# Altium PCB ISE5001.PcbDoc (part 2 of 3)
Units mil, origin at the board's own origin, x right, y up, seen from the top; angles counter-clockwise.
Board outline 2000 x 3000 mil, 4 copper layers (TOP LAYER, L2_GND-PLANE, L3_PWR-PLANE, BOTTOM LAYER), stack 90 mil thick; 187 components, 138 nets, 683 pads, 415 vias.

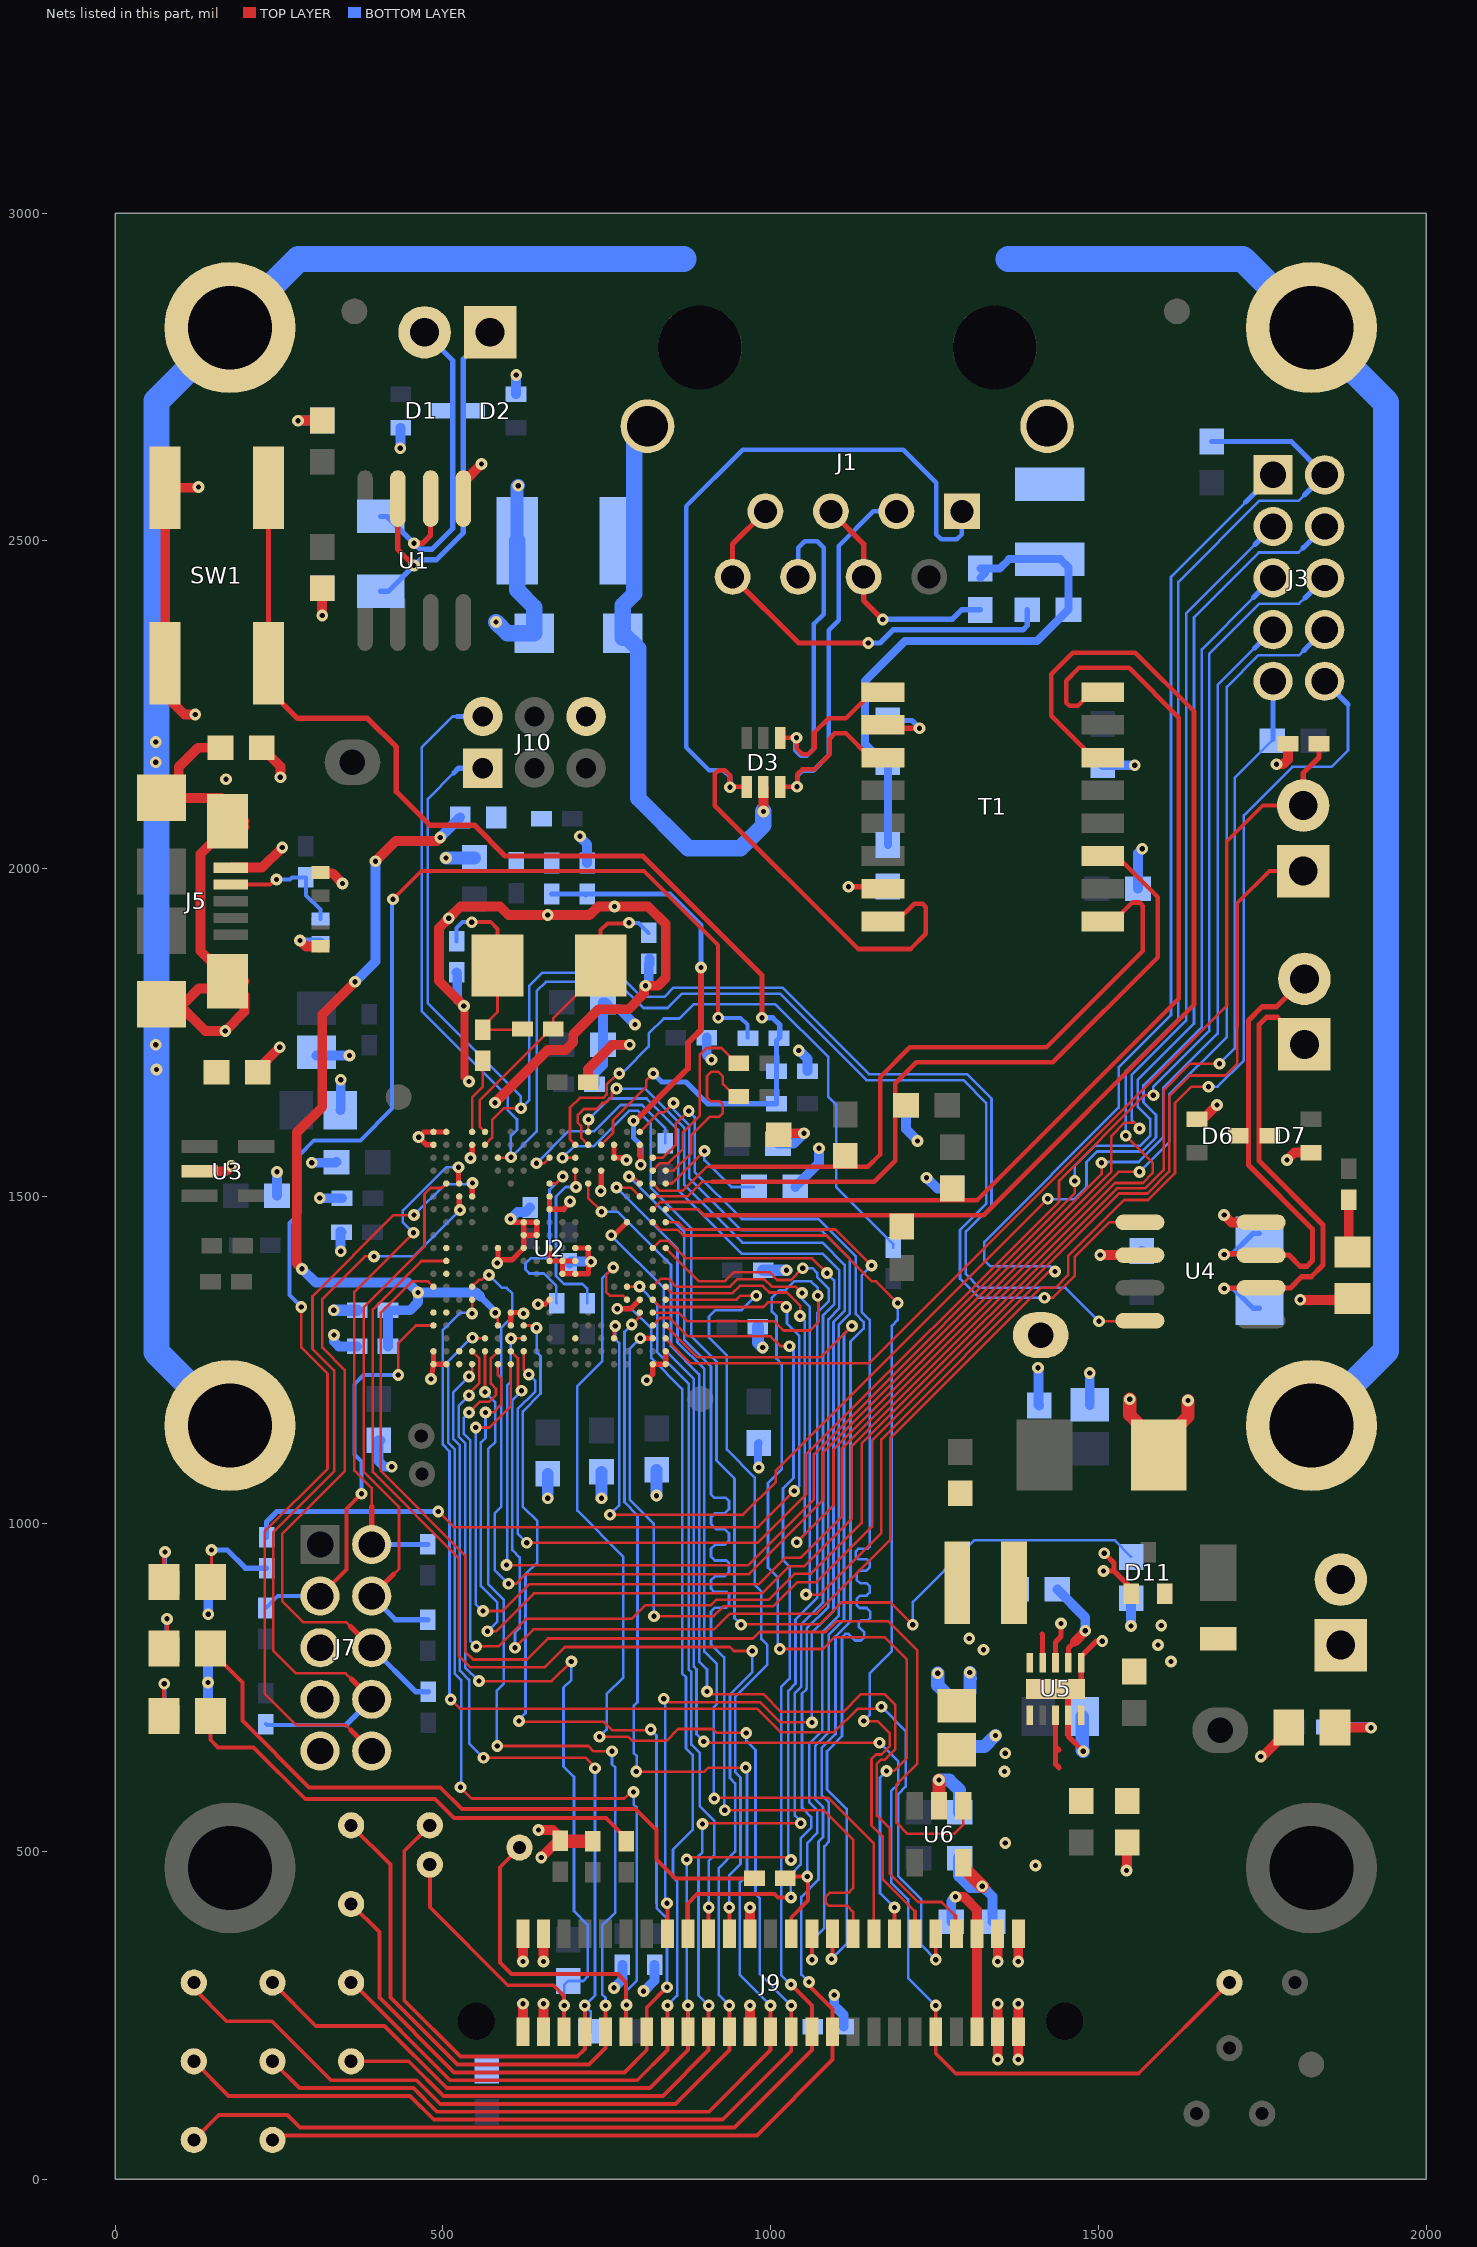
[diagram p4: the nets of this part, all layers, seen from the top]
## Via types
v1: diameter 18, hole 8, TOP LAYER to BOTTOM LAYER, tented both sides, 415 vias

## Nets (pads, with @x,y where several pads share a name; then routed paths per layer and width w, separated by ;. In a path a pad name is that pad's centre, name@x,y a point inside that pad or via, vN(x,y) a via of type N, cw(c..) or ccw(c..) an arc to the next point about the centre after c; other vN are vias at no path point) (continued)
\EXTDBG\: J7.3 R18.2 U2.A4 | length 630.6
  TOP LAYER w4: v1(432,1227) 432,1276 458.68,1302.68 U2.A4@485.55,1302.68
  TOP LAYER w6: J7.3@312.63,889.74 353,930.11 353,1023 v1(376,1046)
  BOTTOM LAYER w6: R18.2@230,871.62 248,889.62 312.51,889.62 J7.3@312.63,889.74 ; v1(376,1046) 376,1095 365,1106 365,1213 379,1227 v1(432,1227)
\HIB\: R49.1 U2.M17 | length 1723.2
  TOP LAYER w4: v1@685.42,1558.58 U2.M17@702.09,1558.58 ; v1@957,847 1075,847 1108,880 1183,880 v1(1217,846)
  BOTTOM LAYER w4: v1(682.42,1558.58) 699.84,1576 730,1576 784,1630 798,1630 817,1611 817,1512.84 879,1450.84 879,1286 917.38,1247.62 917.38,1096.62 945,1069 945,856 v1(955,846) ; v1(1217,846) 1222,846 1217,851 1217,881 1311,975 1524.5,975 R49.1@1550,949.5
\RESET\: C19.1 R38.1 R39.2 SW1.1 SW1.3 U2.P18 | length 1831.4
  TOP LAYER w4: U2.P18@741.46,1578.27 752.72,1589.53 759.47,1596.28 759.47,1616 810.24,1666.76 810.24,1676.24 v1(821,1687)
  TOP LAYER w8: SW1.1@233.74,2562.86 SW1.3@233.74,2313.14 233.74,2273.26 278,2229 385,2229 429,2185 429,2117 480,2066 548,2066 595,2019 805,2019 987,1837 v1(987,1772)
  BOTTOM LAYER w4: R38.1@1012.72,1740.79 R38.1@1014.09,1742.17
  BOTTOM LAYER w8: v1(821,1687) 834,1674 871,1674 904.21,1640.79 R39.2@1009.09,1640.79 C19.1@1009.09,1690.79 1009.09,1737.17 R38.1@1012.72,1740.79 ; v1(987,1772) 1003.38,1772 1014.09,1761.29 R38.1@1014.09,1742.17
\WAKE\: R32.1 R33.2 U2.U18 | length 692
  TOP LAYER w8: U2.U18@800.51,1578.27 800.51,1561.99 802.22,1560.29 802,1560.07 v1(802,1548)
  TOP LAYER w9: v1(791,1615) 794,1615 874,1695 874,1734 894,1754 v1(894,1849)
  BOTTOM LAYER w8: R33.2@666,1961 717,1961 R32.1@718.5,1959.5 ; R32.1@720,1961 846,1961 894,1913 v1(894,1849) ; v1(791,1615) 791,1589 802,1578 v1(802,1548)
ADC0: J3.10 U2.G2 | length 2820.6
  TOP LAYER w4: U2.G2@603.66,1263.31 614.58,1252.39 614.58,1208.42 v1(620,1203) ; v1(610,811) 638,839 914,839 938,863 1070,863 1183,976 1183,1131.21 1411.79,1360 1434.69,1360 1454,1379.31 1454,1408.75 1539.25,1494 1576,1494 1617,1535 1617,1642.03 1641.97,1667 v1(1668,1667)
  BOTTOM LAYER w4: v1(610,811) 610,834 617,841 617,949 606,960 606,1189 v1(620,1203) ; v1(1668,1667) 1682,1667 1722,1707 1722,2081 1796,2155 1856,2155 1881,2180 1881,2249.89
  BOTTOM LAYER w8: J3.10@1845.37,2285.52 1881,2249.89
ADC1: J3.8 U2.G1 | length 2736.8
  TOP LAYER w4: v1(550,1147) 571,1147 603.66,1179.66 U2.G1@603.66,1243.62 ; v1(561,867) 591,867 632,908 982,908 1022,948 1046,948 1109,1011 1109,1115.15 1530.85,1537 v1(1563,1537)
  BOTTOM LAYER w4: v1(550,1147) 550,878 v1(561,867) ; v1(1563,1537) 1608,1582 1608,1655 1696,1743 1696,2277 1744,2325 1806.11,2325 1814.06,2332.94
  BOTTOM LAYER w8: 1814.06,2332.94 J3.8@1845.37,2364.26
ADC2: J3.6 U2.H2 | length 2549.2
  TOP LAYER w4: U2.H2@623.35,1263.31 623.35,1235.65 v1(631,1228) ; v1(628,971) 980,971 1054,1045 1054,1105.41 1440,1491.41 1440,1523.31 1570.69,1654 v1(1584,1654)
  BOTTOM LAYER w4: v1(628,971) 614,985 614,1175 641,1202 641,1218 v1(631,1228) ; v1@1584,1647 v1(1584,1654) 1584,1667 1669,1752 1669,2327 1746,2404 1806.37,2404 1815.19,2412.81
  BOTTOM LAYER w8: 1815.19,2412.81 J3.6@1845.37,2443
ADC3: J3.4 U2.H3 | length 2784.7
  TOP LAYER w4: v1(597,937) 966,937 1066,1037 1066,1106.1 1464,1504.1 v1(1464,1523) ; v1@602.72,1282.79 602.72,1282.99 U2.H3@623.35,1282.99
  BOTTOM LAYER w4: v1(597,937) 598,937 598,1211.31 603.72,1217.03 v1(603.72,1282.79) ; v1@1464,1518 v1(1464,1523) 1464,1546 1495,1577 1564,1577 1579,1592 1579,1618 1560,1637 1560,1677 1646,1763 1646,2383 1745,2482 1805.63,2482 1812.82,2489.18
  BOTTOM LAYER w8: 1812.82,2489.18 J3.4@1845.37,2521.74
CAN0RX: J9.18 TP7.1 U2.W10 | length 2386.6
  TOP LAYER w4: U2.W10@839.88,1420.79 890.67,1370 930,1370 944,1384 998,1384 1010,1372 1031,1372 v1(1049,1390) ; v1(872,488) 872,491 1031,491 v1(1031,487)
  TOP LAYER w6: TP7.1@240,300 306,234 410.88,234 505.88,139 816.02,139 874.02,197 J9.18@874.02,225.2 v1(874.02,264.96)
  BOTTOM LAYER w4: v1(872,488) 872,266.98 v1(874.02,264.96) ; v1(1031,487) 1027,491 1027,745 1038,756 1038,854 1071,887 1071,1322 1089,1340 1089,1358.29 1071,1376.29 1071,1383 1064,1390 v1(1049,1390)
CAN0TX: J9.20 TP14.1 U2.V10 | length 2288.7
  TOP LAYER w4: U2.V10@820.2,1420.79 831.2,1431.79 844.33,1431.79 871.11,1405 1063.5,1405 v1(1086,1382.5) ; v1(896,542) 891,542 892,543 v1(1046,543) v1@1049,543
  TOP LAYER w6: TP14.1@360,180 447.91,180 500.91,127 835.51,127 905.51,197 J9.20@905.51,225.2 v1(905.51,264.96)
  BOTTOM LAYER w4: v1(896,542) 891,542 896,537 896,498.69 890.31,493 890,493 890,280.47 v1(905.51,264.96) ; v1(1046,543) 1049,543 1037,555 1037,742 1047,752 1047,847 1080,880 1080,1318 1097,1335 1097,1371.5 v1(1086,1382.5)
CAN1RX: J10.1 U2.E18 U4.4 | length 2308.8
  TOP LAYER w4: U2.E18@564.29,1578.27 575.21,1589.19 575.21,1616.43 592.79,1634 v1(619,1634) ; v1(1501,1309) 1532.11,1309 1538.11,1315 1558.48,1315 U4.4@1563.48,1310
  BOTTOM LAYER w4: 517,2146 477,2106 477,1794 619,1652 v1(619,1634) 632,1647 632,1821 652,1841 766,1841 803,1804 838,1804 852,1818 1018,1818 1150,1686 1300,1686 1337,1649 1337,1485 1298,1446 1298,1381 1319,1360 1450,1360 v1(1501,1309)
  BOTTOM LAYER w8: 517,2146 524,2153 J10.1@561,2153
CAN1TX: J10.2 U2.F17 U4.1 | length 2514.6
  TOP LAYER w4: U2.F17@583.98,1558.58 603.01,1558.58 v1(603.72,1559.29) ; v1(1418,1345) 1431,1345 1464,1378 1464,1407.43 1516.57,1460 U4.1@1563.48,1460
  BOTTOM LAYER w4: 522,2231.74 514.74,2231.74 468,2185 468,1782 599,1651 599,1631 613,1617 613,1601 603.72,1591.72 v1(603.72,1559.29) 643,1598.57 643,1813 657,1827 766,1827 806,1787 843,1787 865,1809 1014,1809 1146,1677 1294,1677 1329,1642 1329,1488.31 1289,1448.31 1289,1374 1318,1345 v1(1418,1345)
  BOTTOM LAYER w8: 522,2231.74 J10.2@561,2231.74
CANH: D6.3 J6.2 R45.2 U4.7 | length 732.9
  TOP LAYER w8: v1(1692,1411) 1693,1412 1746.52,1412 U4.7@1748.52,1410 1791,1410 1808,1393 1818.37,1393 1827,1401.63 1827,1449.37 1729,1547.37 1729,1768 1750,1789 1772,1789 J6.2@1814.49,1831.49
  BOTTOM LAYER w8: v1(1692,1411) 1692.5,1411.5 1704.5,1411.5 1736.09,1443.09 R45.2@1746,1443.09
CANL: D7.3 J6.1 R45.1 U4.6 | length 730.8
  TOP LAYER w8: v1(1692,1359) 1693,1359 1694,1360 U4.6@1748.52,1360 1793,1360 1810,1377 1825,1377 1843,1395 1843,1456 1745,1554 1745,1761.37 1756.63,1773 1772.97,1773 J6.1@1814.49,1731.49
  BOTTOM LAYER w8: v1(1692,1359) 1706,1359 1736.09,1328.91 R45.1@1746,1328.91
CHGND: C3.2 C8.2 C9.1 D3.2 H1.1 H2.1 H3.1 H4.1 J1.SH1 J1.SH2 J5.6 J5.7 J5.8 J5.9 R7.1 R28.1 | length 6482.7
  TOP LAYER w15: J5.9@97,1792.52 137.52,1752 v1(168,1752) 197.39,1781.39 197.39,1806.61 J5.7@186.72,1817.28 ; J5.9@108,1797 127.48,1816.48 127.48,1817 186.44,1817 J5.7@186.72,1817.28 ; C3.2@160.5,2184 126,2184 97,2155 97,2107.48 161.96,2107.48 J5.6@197.39,2072.05 ; J5.7@197.39,1827.95 J5.7@186.72,1817.28 ; J5.6@197.39,2063.39 171.39,2063.39 130,2022 130,1874 173.72,1830.28 J5.7@186.72,1817.28 ; v1(989,2087) D3.2@989,2124.5
  BOTTOM LAYER w20: J1.SH1@797,2655 J1.SH1@797,2666.73
  BOTTOM LAYER w25: R28.1@774.5,2352 R28.1@774.5,2359 ; J1.SH1@797,2655 791.74,2649.74 791.74,2500 792,2499.74 792,2419 774.5,2401.5 R28.1@774.5,2359 ; v1(989,2087) 989,2066 954,2031 874,2031 798,2107 798,2335.5 R28.1@774.5,2359
  BOTTOM LAYER w40: H3.1@175,1150 63,1262 v1(63,1693) 63,2713 H1.1@175,2825 280,2930 867,2930 ; 1363,2930 1720,2930 H2.1@1825,2825 1939,2711 1939,1264 H4.1@1825,1150
  other v1: 62,1731 169,2136 62,2162 62,2193
COL: J9.15 U2.N18 | length 1967
  TOP LAYER w4: U2.N18@721.77,1578.27 710.85,1589.19 710.85,1606.94 706,1611.79 706,1624 715,1633 734.31,1633 743.31,1642 748.18,1642 758,1651.82 758,1656.69 765,1663.69 v1(765,1664) ; v1(837,733) 838,733 843,728 984,728 1015,697 v1(1063,697)
  TOP LAYER w6: v1(842,421) 842.52,420.48 J9.15@842.52,374.8
  BOTTOM LAYER w4: v1(765,1664) 808.47,1664 868,1604.47 868,1518 957,1429 1079,1429 1113,1395 1113,1325 1096,1308 1096,867 1063,834 v1(1063,697) ; v1(837,733) 839,731 839,424 v1(842,421) v1@842,415.09
CRS: J9.17 U2.N19 | length 1793.8
  TOP LAYER w4: U2.N19@721.77,1597.95 v1@721.77,1623
  TOP LAYER w6: J9.17@874.02,374.8 874.02,421.02 888,435 1006,435 1011,430 v1(1031,430)
  BOTTOM LAYER w4: v1(722,1617) 754,1649 811,1649 859,1601 859,1509 956,1412 1079.69,1412 1105,1386.69 1105,1329 1088,1312 1088,873 1055,840 1055,748.69 1054.5,748.19 1054.5,747.5 1048,741 1048,567 1062,553 1062,536 1046,520 1046,480 1031,465 v1(1031,430)
DEBUG_RX: J4.1 U2.V3 | length 2213.8
  TOP LAYER w4: v1(822,859) 913,859 928,874 1004,874 1041,911 1070,911 1155,996 1155,1127.21 1531.79,1504 1574.69,1504 1608,1537.31 1608,1652 1640,1684 1694,1684 1712,1702 1712,1759
  TOP LAYER w6: 1712,1759 1712,1947 1760.92,1995.92 J4.1@1812.68,1995.92
  TOP LAYER w8: v1@802.22,1282.29 802.92,1282.99 U2.V3@820.2,1282.99
  BOTTOM LAYER w4: v1(801.22,1283.29) 785,1267.07 785,1037 822,1000 v1(822,859)
DEBUG_TX: J4.2 R3.2 U2.W3 | length 1591.3
  TOP LAYER w4: U2.W3@839.88,1282.99 877.87,1245 1149.79,1245 1696,1791.21
  TOP LAYER w6: 1696,1791.21 1696,2041 1750.92,2095.92 J4.2@1812.68,2095.92
  TOP LAYER w8: J4.2@1812.68,2095.92 1812.68,2145.55 1836.62,2169.5 R3.2@1836.62,2190
EN0INTRN: J9.41 U2.D6 | length 1804.8
  TOP LAYER w4: v1(512,732) 526,718 979,718 1015,682 1097,682 1133,718 1166,718 v1(1169,721) ; U2.D6@544.61,1342.05 v1@544.7,1324.76
  TOP LAYER w6: v1(1251.97,335.04) J9.41@1251.97,374.8
  BOTTOM LAYER w4: v1(512,732) 510,734 510,1110.69 500,1120.69 500,1296 526,1322 543,1322 v1(544.22,1320.79) ; v1(1169,721) 1206,684 1206,599 1195,588 1195,462 1230,427 1230,357.01 v1(1251.97,335.04)
EN0RREF_CLK: R43.1 U2.M18 | length 909
  TOP LAYER w4: U2.M18@702.09,1578.27 694,1586.35 694,1635 709,1650 744.87,1650 750,1655.13 750,1670.21 764,1684.21 v1@764,1691
  BOTTOM LAYER w4: v1@764,1691 777,1691 814,1728 814,1748 837,1771 861,1771 883,1793 1007,1793 1088,1712 1088,1651.48 1100,1639.48 1100,1514 1187,1427 R43.1@1187,1421.62
  other v1: 769,1687
EN0RX+: R13.2 T1.6 U2.W13 | length 1827
  TOP LAYER w4: U2.W13@839.88,1479.84 890.16,1479.84 899,1471
  TOP LAYER w7: 899,1471 1325,1471 1646,1792 1646,1820 1646,2237 1646,2239.53 1556.53,2329 1461,2329 1428,2296 1428,2233 1492,2169 T1.6@1506.52,2169
EN0RX-: R11.2 T1.8 U2.V13 | length 1675.9
  TOP LAYER w4: U2.V13@820.2,1479.84 831.35,1491 897,1491 900,1494
  TOP LAYER w7: 900,1494 1315.47,1494 1623,1801.53 1623,2230 1547,2306 1470.53,2306 1451,2286.47 1451,2253 1456,2248 1469,2248 1490,2269 T1.8@1506.52,2269
EN0TX+: R10.2 T1.1 U2.V15 | length 1117.8
  TOP LAYER w4: U2.V15@820.2,1519.21 831.5,1507.91 865.91,1507.91 903,1545 910,1545
  TOP LAYER w7: 910,1545 1148.47,1545 1167,1563.53 1167,1679 1167,1681.53 1212.47,1727 1215,1727 1421,1727 1568,1874 1568,1943 1563,1948 1552,1948 1523,1919 T1.1@1506.52,1919
EN0TX-: R9.2 T1.3 U2.V14 | length 1192.2
  TOP LAYER w4: U2.V14@820.2,1499.53 873.53,1499.53 896,1522 910,1522
  TOP LAYER w7: 911,1522 1158,1522 1190,1554 1190,1672 1222,1704 1428,1704 1430.53,1704 1591,1864.47 1591,1956 1528,2019 T1.3@1506.52,2019
EN0TXER: J9.42 TP9.1 U2.T12 | length 2169.1
  TOP LAYER w4: v1(898,668) 900,666 v1(1166,666)
  TOP LAYER w6: v1(1251.97,264.96) J9.42@1251.97,225.2 1251.97,192.03 1283,161 1561,161 TP9.1@1700,300
  TOP LAYER w8: v1(756.72,1440.29) 760.96,1440.29 U2.T12@780.83,1460.16
  BOTTOM LAYER w4: v1(756.72,1440.29) 837,1360 837,1267 883,1221 883,782 887,778 887,679 v1(898,668) ; v1(1166,666) 1195,637 1195,603 1184,592 1184,453 1210,427 1210,306.93 v1(1251.97,264.96)
GND: C1.2 C2.2 C3.1 C4.2 C5.2 C6.2 C7.2 C9.2 C10.2 C11.2 C12.2 C13.2 C14.1 C15.2 C16.2 C17.2 C18.2 C19.2 C20.2 C21.2 C22.2 C23.2 C24.2 C25.2 C26.2 C27.2 C28.2 C29.2 C30.1 C31.2 C32.2 C33.2 C34.2 C35.2 C36.2 C37.2 C38.2 C39.2 C40.2 C41.2 C42.2 C43.2 C44.2 C45.1 C46.1 C47.1 C48.1 D1.1 D2.1 D4.2 D5.2 D6.1 D7.1 D8.1 D9.2 D11.1 D15.1 D16.2 J5.5 J7.5 J7.7 J7.9 J8.1 J9.23 J9.24 J9.47 J9.48 J9.49 J9.50 J10.6 R3.1 R7.2 R22.2 R28.2 R32.2 R37.1 R41.2 R42.1 R50.2 R53.2 R55.2 R60.1 SW1.2 SW1.4 TL1.1 U1.5 U2.A1 U2.A2 U2.A18 U2.A19 U2.B1 U2.B19 U2.D18 U2.F10 U2.G4 U2.G5 U2.H10 U2.H11 U2.H12 U2.J11 U2.J12 U2.K6 U2.K9 U2.K10 U2.K13 U2.K14 U2.L8 U2.L9 U2.M8 U2.M9 U2.M10 U2.N10 U2.P16 U2.R17 U2.R18 U2.V1 U2.W1 U2.W2 U3.2 U4.2 U4.8 U5.1 U5.4 U5.6 U5.11 U6.2 | length 7010
  TOP LAYER w8: v1(482,1221) U2.A1@485.55,1243.62 ; U2.A2@485.55,1263.31 U2.A1@485.55,1243.62 ; U2.A18@485.55,1578.27 474.73,1578.27 v1(463,1590) 470.95,1597.95 U2.A19@485.55,1597.95 U2.B19@505.24,1597.95 ; U2.B1@505.24,1243.62 U2.A1@485.55,1243.62 ; v1(542,1558) 541,1557 541,1559 544.61,1562.61 U2.D18@544.61,1578.27 ; v1(583,1398) 583.98,1398.98 v1@583.98,1402.79 ; U2.F10@583.98,1420.79 v1@583.98,1402.79 ; v1(603,1465) 607.84,1460.16 U2.H12@623.35,1460.16 ; U2.G4@603.66,1302.68 U2.G5@603.66,1322.36 621.36,1322.36 623,1324 v1(623,1321) ; v1(645,1335) 655.67,1335 U2.K6@662.72,1342.05 ; U2.K10@662.72,1420.79 U2.K9@662.72,1401.1 U2.L9@682.4,1401.1 ; U2.K14@663.46,1498.79 U2.K14@662.72,1499.53 U2.K13@662.72,1479.84 684.16,1479.84 ; 684.72,1479.29 684.16,1479.84 ; v1(694,1492) 694,1490 684,1480 684.16,1479.84 ; U2.M9@702.09,1401.1 U2.L9@682.4,1401.1 ; U2.M10@702.09,1420.79 U2.N10@721.77,1420.79 v1@721.77,1404.23 ; v1@724.9,1401.1 722,1398.2 722,1382 721.42,1381.42 U2.M8@702.09,1381.42 U2.L8@682.4,1381.42 U2.L9@682.4,1401.1 ; v1(741,1508) 741.46,1508.46 U2.P16@741.46,1538.9 ; U2.R18@761.14,1578.27 U2.R17@761.14,1558.58 776.42,1558.58 v1(780,1555) ; v1(811,1219) 820,1228 820.2,1227.8 U2.V1@820.2,1243.62 U2.W1@839.88,1243.62 U2.W2@839.88,1263.31 ; U5.11@1434.7,748 U5.11@1438,748 ; v1(1477,653) 1454.4,675.6 U5.4@1454.4,708 1454.4,741.6 1474.1,761.3 U5.6@1474.1,788 1474.1,798.1 1497,821 v1(1506,821) ; v1(1508,928) 1524,928 ; v1(1509,955) 1524,940 1524,928 ; D11.1@1550.41,893.5 1550.41,901.59 1524,928 ; v1@583.98,1402.79 605.35,1402.79 U2.H10@623.35,1420.79 U2.H11@623.35,1440.47 ; U2.H11@623.35,1440.47 U2.J11@643.03,1440.47 U2.J12@643.03,1460.16 U2.H12@623.35,1460.16 ; U2.H11@623.35,1440.47 U2.H12@623.35,1460.16
  TOP LAYER w12: v1(532,1790) 533,1789 533,1682 v1(540,1675)
  TOP LAYER w15: v1(122,2235) 106,2235 76.26,2264.74 SW1.4@76.26,2313.14 SW1.2@76.26,2580.86 125.86,2580.86 v1(127,2582) ; U3.2@128.7,1538 169,1538 v1(177,1546) ; J5.5@176.32,2001.18 224.18,2001.18 v1(255,2032) ; R7.2@217.5,1689 217.5,1693.5 v1(251,1727) ; C3.1@223.5,2184 252,2155.5 v1(252,2139) ; v1@280,2683 280.5,2683.5 C1.2@316,2683.5 C1.2@320,2683.5 ; v1(282,1890) 291,1881 311.28,1881 D5.2@313,1879.28 ; D4.2@313,1992.72 331.28,1992.72 v1(347,1977) ; v1(316,2386) C2.2@316,2427.5 ; v1@343.62,1677 v1(344.15,1677.53) ; v1(357.46,1714.54) v1@358,1714 ; U1.5@531.22,2564.28 531.22,2589.22 v1(559,2617) ; v1(532,1790) 494,1828 494,1909 v1(509,1924) 527,1942 586.99,1942 599.99,1929 v1(660,1929) 724.01,1929 737.01,1942 v1(762,1942) 813,1942 840,1915 840,1833 828,1821 v1(809,1821) 807,1821 807,1809 783,1785 737,1785 699,1747 699,1735 687,1723 660,1723 v1(579.5,1642.5) ; v1(646,533) 668,533 679,522 C45.1@679,516.62 ; v1(650,491) 676,517 678.62,517 C45.1@679,516.62 ; C45.1@679.5,516.5 C45.1@679.31,516.31 ; C45.1@682.81,512.81 680,515.62 C45.1@679.31,516.31 ; C4.2@721.62,1674 721.62,1693.62 759,1731 v1(785,1731) ; J9.24@968.5,225.2 v1(968.5,264.96) ; J9.23@968.5,374.8 v1(968.5,414.57) ; C5.2@1012.5,1594 1012.5,1596 v1(1051,1596) ; v1(1346.46,182.7) J9.48@1346.46,225.2 v1(1346.46,267.69) ; v1(1346.46,332.31) J9.47@1346.46,374.8 ; v1(1377.95,182.7) J9.50@1377.95,225.2 v1(1377.95,267.69) ; v1(1377.95,332.31) J9.49@1377.95,374.8 ; v1(1503,1410) U4.2@1563.48,1410 ; v1(1543,471) 1543,477.5 1544,478.5 R22.2@1544,514 ; v1(1555.5,2157.5) v1@1556,2158 ; D6.1@1650.5,1617.59 1659.59,1617.59 v1(1681,1639) ; v1(1692,1471) 1703,1460 U4.8@1748.52,1460 ; v1(1748,645) 1748,643 1790.57,685.57 D15.1@1790.57,689 ; v1(1772,2159) 1782,2159 1789.38,2166.38 R3.1@1789.38,2190 ; v1(1788,1555) 1799.41,1566.41 D7.1@1824.5,1566.41 ; v1(1808,1342) 1808.43,1341.57 D8.1@1888,1341.57 ; C45.1@679,516.62 C45.1@679.31,516.31
  TOP LAYER w20: C45.1@680,515.62 C46.1@729,515.62 ; U6.2@1257,570 v1(1257,609) ; v1(1548,1190) 1548,1166 1592.01,1121.99 D9.2@1592.01,1119.01 ; D9.2@1588,1105 D9.2@1592.01,1109.01 ; D9.2@1592.01,1105 D9.2@1592.01,1109.01 ; v1(1637,1188) 1637,1164 D9.2@1592.01,1119.01 ; D9.2@1592.01,1109.01 D9.2@1592.01,1119.01
  BOTTOM LAYER w8: v1@542,1556 v1(542,1558) ; v1@1507,927 v1(1508,928) ; v1(1509,955) v1@1509,958
  BOTTOM LAYER w12: v1(982,1086) 981,1087 981,1122.5 C41.2@982,1123.5
  BOTTOM LAYER w15: R55.2@141.5,705 v1(141.5,758) R53.2@141.5,808 ; R50.2@141.5,909 R50.2@142,909.5 ; v1(142,862) R50.2@142,909.5 ; R42.1@246.8,1500.6 246.8,1536.8 v1(247,1537) ; v1(279,2683) 279.5,2683.5 C7.2@316,2683.5 C7.2@322,2683.5 ; v1(282,1890) 284.72,1887.28 D16.2@313,1887.28 ; v1(300,1551) 336.5,1551 C25.2@337.5,1552 ; C17.2@307,1714.54 v1(357.46,1714.54) ; v1@312,1496.79 C26.2@346.09,1496.79 ; v1(316,2386) C10.2@316,2427.5 ; v1(334,1288) 334,1278 341.21,1270.79 C34.2@369.09,1270.79 ; C21.2@343.46,1631 344.15,1631.69 v1(344.15,1677.53) ; v1(344,1416) 344,1446.38 C29.2@345.38,1445 ; C35.2@402,1127.5 C35.2@402,1124.5 ; C35.2@405,1127.5 C35.2@402,1124.5 ; v1(422,1087) 411,1087 402,1096 C35.2@402,1124.5 ; v1(435,2641) 435.5,2641.5 D1.1@435.5,2672.41 ; C15.2@521,1841.38 522,1840.38 522,1800 v1(532,1790) ; v1(603,1465) 614,1476 626.38,1476 C27.2@633,1482.62 ; D2.1@611.5,2723.59 v1@611.5,2753 ; C28.2@693,1397.38 695.62,1400 v1(726,1400) ; v1(709,2049) 709,2048 720,2037 R32.2@720,2008.24 ; C20.2@731.34,1670.79 731.34,1687.33 744.21,1700.2 C18.2@744.21,1730.79 C18.2@744.21,1731 ; v1(761,292) 774,305 C47.1@774,327.38 ; v1(785,1731) C18.2@744.21,1731 ; v1(793,1762) 770,1785 758,1785 747.21,1795.79 C16.2@744.21,1795.79 C18.2@744.21,1731 ; v1(806,287) 806,286 823,303 C48.1@823,327.38 ; v1(809,1821) 814,1826 C14.1@814,1854.38 ; C14.1@815,1854.38 C14.1@815,1862.38 ; R37.1@902.62,1742 902.62,1715.38 v1(910,1708) ; C23.2@1011.21,1579.79 1034.79,1579.79 v1(1051,1596) ; R41.2@1037.5,1514 1074,1550.5 v1(1074,1573) ; v1(1043,1722) 1043,1723 1056.34,1709.66 C19.2@1056.34,1690.79 ; v1(1097,281) 1097,265 1105.48,256.52 ; 1105.48,256.47 1111.62,250.33 R60.1@1111.62,233 ; C22.2@1206.5,1639 1206.5,1602.5 1224,1585 v1(1224,1584) ; v1(1238,1528) 1254.5,1511.5 C24.2@1277,1511.5 ; v1(1408,1238) 1409,1238 1409,1181.5 C37.2@1410,1180.5 ; C36.2@1487,1181.46 v1(1487,1230) ; v1(1503,1410) 1559.5,1410 C30.1@1566,1416.5 ; C11.2@1507,2157.5 v1(1555.5,2157.5) ; C13.2@1560.5,1969 1560.5,2023.5 v1(1567,2030) ; R50.2@142,909.5 143,910.5 142,911.5 R50.2@142,909.5
  BOTTOM LAYER w18: v1(333.59,1325.79) C32.2@369.09,1325.79 ; v1(660,1039) C40.2@660,1076.5 ; v1(742,1039) C39.2@742,1079.5 ; v1(826,1043) C38.2@826,1082.5 ; C33.2@980.62,1301 980.62,1276.38 v1(988,1269) ; C31.2@988.62,1387 v1(1024.13,1387)
  BOTTOM LAYER w20: v1(504.84,2015.83) C12.2@548.21,2015.83 ; C9.2@613.26,2500 613.26,2582.26 v1(615,2584) ; v1(1257,609) 1273,609 1288.5,593.5 C44.2@1288.5,560 ; C42.2@1285,660.5 1326.5,660.5 v1(1343,677) ; C43.2@1475.56,706.1 1475.56,654.44 v1(1477,653)
  BOTTOM LAYER w25: v1(581,2376) 598,2359 R28.2@639.5,2359 639.5,2398.5 613.26,2424.74 C9.2@613.26,2500
  other v1: 1404,478.5 1358,513 1357,622 1358,650 312,1497 612,2753
I2C6SCL: J3.9 R2.2 U2.F2 | length 2756.9
  TOP LAYER w4: v1(540,1170) 556,1186 570.5,1186 581,1196.5 581,1206 573.06,1213.94 573.06,1252.39 U2.F2@583.98,1263.31 ; v1(551,813) 585,813 627,855 788,855 809,876 909,876 917,884 997,884 1037,924 1062,924 1139,1001 1139,1122.53 1528.47,1512 1571.37,1512 1600,1540.63 1600,1662 1640,1702 v1(1685,1702)
  BOTTOM LAYER w4: v1(540,1170) 532,1162 532,1137 542,1127 542,821 v1@550.5,812.5 ; v1(1685,1702) 1708,1725 1708,2138 R2.2@1766.63,2196.63
  BOTTOM LAYER w8: R2.2@1766.63,2196.63 J3.9@1766.63,2285.52
I2C6SDA: J3.2 R1.2 U2.F1 | length 3252.3
  TOP LAYER w4: v1(565,1170) 577,1170 589,1182 589,1221.68 583.98,1226.7 U2.F1@583.98,1243.62 ; v1(568,836) 581,836 639,894 987,894 1028,935 1051,935 1124,1008 1124,1118.84 1525.16,1520 1568.06,1520 1583,1534.94 1583,1551 v1(1542,1592)
  BOTTOM LAYER w4: v1(565,1170) 565,1131 558,1124 558,905 583,880 583,851 v1(568,836) ; v1(1542,1592) 1542,1691 1622,1771 1622,2437 1746,2561 1805.89,2561 1814.44,2569.56
  BOTTOM LAYER w8: R1.2@1673,2651.5 1794.35,2651.5 J3.2@1845.37,2600.48 1814.44,2569.56
I2C8SCL: J9.6 R59.2 TP4.1 U2.D2 | length 1641.8
  TOP LAYER w4: v1(540,1196) 540,1199.21 555.72,1214.93 555.72,1252.2 U2.D2@544.61,1263.31 ; v1(555,760) 666,760 v1(696,790)
  TOP LAYER w6: TP4.1@480,480 480,415 599,296 668.53,296 685.04,279.49 v1(685.04,264.96) J9.6@685.04,225.2
  BOTTOM LAYER w4: v1(540,1196) 524,1180 524,1133 534,1123 534,781 v1(555,760) ; v1(685.04,264.96) 685.04,296.54 R59.2@691,302.5 714.5,302.5 721,309 721,388 700.04,408.96 700.04,613.96 684,630 684,750 696,762 v1(696,790)
I2C8SDA: J9.8 R61.2 TP2.1 U2.D1 | length 1886.8
  TOP LAYER w4: v1(540,1225) 544.61,1229.61 U2.D1@544.61,1243.62 ; v1(562,643) 718,643 733,628 v1(732,627)
  TOP LAYER w6: TP2.1@480,540 441,501 441,272.97 526.97,187 705,187 716.54,198.54 J9.8@716.54,225.2 v1(716.54,264.96)
  BOTTOM LAYER w4: v1(540,1225) 516,1201 516,1129.37 526,1119.37 526,776 540,762 540,665 v1(562,643) ; R61.2@725.5,226 725.5,255.99 v1(716.54,264.96) 732,280.43 v1(732,627)
LED0: D13.2 R24.2 | length 1035
  TOP LAYER w6: D13.2@144.46,806.03 145.97,806.03 194,758 194,700 296,598 496,598 529,565 794,565 826,533 826,488 855,459 R24.2@975.38,459
LED1: D14.2 R23.2 | length 737.5
  TOP LAYER w4: R23.2@779.53,515.62 R23.2@779.53,520.47
  TOP LAYER w6: D14.2@145.43,707 145.43,670.57 157,659 211,659 290,580 488,580 517,551 749,551 R23.2@779.53,520.47
LED2: D12.2 R48.2 | length 147.1
  TOP LAYER w4: D12.2@144,911 147,914 v1(147,960)
  TOP LAYER w6: D12.2@144,911 D12.2@145.43,911
  BOTTOM LAYER w8: v1(147,960) 171,960 198.62,932.38 R48.2@231,932.38
MCU_ISENSE: U2.A7 U6.1 | length 1831.7
  TOP LAYER w4: U2.A7@485.55,1361.73 477.28,1370 453,1370 405,1322 405,1081 534,952 534,805.31 546.31,793 628,793 660,825 973,825 983,835 1084,835 1100.31,851.31 1179.69,851.31 1224,807 1224,634 1213,623 ; 1203,613 1192,602 1192,544 1209,527 1280,527 1294,541 U6.1@1294,570 ; 1203,613.04 1212.96,623
MDC: J9.21 U2.W6 | length 1234.7
  TOP LAYER w4: U2.W6@839.88,1342.05 948,1342.05 953.95,1348 v1(978,1348)
  TOP LAYER w6: J9.21@937.01,374.8 v1(937.01,414.57)
  BOTTOM LAYER w4: v1(937.01,414.57) 937.01,464.01 954,481 954,613 946,621 946,736 995,785 995,815 986,824 986,897 976,907 976,1071 975.79,1071 933.38,1113.41 933.38,1256.62 906,1284 906,1316 915.91,1325.91 955.91,1325.91 v1(978,1348)
MDIO: J9.19 U2.T7 | length 1056.8
  TOP LAYER w4: U2.T7@781.09,1362 v1(800,1362)
  TOP LAYER w6: J9.19@905.51,374.8 v1(905.51,414.57)
  BOTTOM LAYER w4: v1(800,1362) 827,1335 827,1262 875,1214 875,778 879,774 879,663 892,650 892,569 914,547 914,494 905.51,485.51 v1(905.51,414.57)
MOSC0: C14.2 R5.1 U2.E19 Y1.1 | length 472.5
  TOP LAYER w4: U2.E19@564.29,1597.95 556,1606.24 556,1646 668.62,1758.62 668.62,1771.62 740.74,1843.74 Y1.1@740.74,1852
  TOP LAYER w6: Y1.1@740.74,1852 740.74,1905.74 751,1916 782,1916 v1@784,1914
  BOTTOM LAYER w6: v1(784,1917) 798.62,1917 C14.2@814,1901.62
MOSC1: R4.2 U2.D19 | length 115.2
  TOP LAYER w4: U2.D19@544.61,1597.95 544.61,1650.61 561,1667 R4.2@561,1706.38
NetC6_1: C6.1 C42.1 L1.2 R16.1 R51.1 U5.10 | length 119.1
  BOTTOM LAYER w20: v1(1255,772) 1255,753.5 C42.1@1285,723.5 1304,742.5 1304,763 1305,764 1304,765 v1(1304,773)
  other v1: 1325,808 1303,825
NetC8_1: C8.1 R26.1 R27.1 R29.1 R34.1 | length 845.1
  BOTTOM LAYER w12: R34.1@1179,2035.5 R29.1@1179,2162.5 1171.5,2162.5 1144,2190 1144,2286 1205,2347 1406.5,2347 R27.1@1454.5,2395 1454.5,2459.5 1442.09,2471.91 C8.1@1426,2471.91 1363.91,2471.91 1349.5,2457.5 R26.1@1320,2457.5 ; R26.1@1320,2443.5 R26.1@1327,2450.5
NetC15_1: C15.1 R4.1 R5.2 Y1.2 | length 319.9
  TOP LAYER w4: Y1.2@583.26,1852 583.26,1781.26 561,1759 R4.1@561,1753.62 620,1753.62 R5.2@621.38,1755
  TOP LAYER w6: v1@541,1918 v1(544,1918) 573,1918 583.26,1907.74 Y1.2@583.26,1852
  BOTTOM LAYER w6: C15.1@521,1888.62 521,1909 530,1918 v1(544,1918) v1@546,1918
NetC32_1: C32.1 C34.1 FB1.2 U2.F4 | length 1292.5
  TOP LAYER w4: U2.F4@583.98,1302.68 v1@583.98,1317.95
  TOP LAYER w15: v1(285,1389) 277,1397 277,1597 316,1636 316,1777 v1(366,1827) ; v1(397,2011) 428,2042 491,2042 v1(496,2047)
  BOTTOM LAYER w10: 557,1347 580,1324 v1(580,1322)
  BOTTOM LAYER w15: v1(285,1389) 306,1368 447,1368 v1(462,1353) ; v1(366,1827) 397,1858 v1(397,2011) ; C34.1@416.34,1270.79 C32.1@416.34,1325.79 449.79,1325.79 462,1338 v1(462,1353) ; v1(496,2047) 496,2047.56 FB1.2@526.44,2078 ; 557,1347 551,1353 v1(462,1353)
NetD8_2: D8.2 R12.2 | length 82.4
  TOP LAYER w15: R12.2@1882,1494.38 1882,1420.43 D8.2@1888,1414.43
NetD10_2: D10.2 D11.2 J8.2
  other v1: 1611,790 1591,815 1596,845
NetD12_1: D12.1 R50.1 | length 97.6
  TOP LAYER w4: v1@74.57,957.57 75,958 v1(76,957)
  TOP LAYER w6: D12.1@74.57,911 v1@74.57,957.57
  BOTTOM LAYER w4: R50.1@76,911.5 R50.1@78.5,909
  BOTTOM LAYER w6: R50.1@76,911.5 v1(76,957)
NetD13_1: D13.1 R53.1 | length 94
  TOP LAYER w4: D13.1@74.57,810 D13.1@79,814.43
  TOP LAYER w6: D13.1@79,814.43 v1(79,855)
  BOTTOM LAYER w4: v1@78.5,853.5 79,854 v1(79,855)
  BOTTOM LAYER w6: R53.1@78.5,808 v1@78.5,853.5
NetD14_1: D14.1 R55.1 | length 101.6
  TOP LAYER w4: v1@74.57,755.57 v1(75,756)
  TOP LAYER w6: D14.1@74.57,707 v1@74.57,755.57
  BOTTOM LAYER w4: R55.1@75,708.5 R55.1@78.5,705
  BOTTOM LAYER w6: R55.1@75,708.5 v1(75,756)
NetD15_2: D15.2 R56.2 | length 123.4
  TOP LAYER w15: D15.2@1861.43,689 v1(1916,689)
  BOTTOM LAYER w15: R56.2@1847.62,690 1915,690 v1(1916,689)
NetD16_1: D16.1 J5.4 R35.1 | length 189.9
  TOP LAYER w6: J5.4@176.32,1975.59 236.59,1975.59 v1@244,1983
  BOTTOM LAYER w6: v1(246,1983) 266.62,1983 270,1986.38 R35.1@291,1986.38 291,1959 313,1937 D16.1@313,1922.72
NetFB1_1: FB1.1 R30.1 R31.2 R33.1
NetJ1_4: J1.4 J1.5 R26.2 | length 358.4
  TOP LAYER w8: J1.5@1092,2544.88 1142,2494.88 J1.4@1142,2444.88 1142,2408.92 v1(1171,2379.92)
  BOTTOM LAYER w8: J1.5@1092,2544.88 J1.5@1096,2540.88 ; v1(1171,2379.92) 1171.08,2380 1277,2380 1291.5,2394.5 R26.2@1320,2394.5
NetJ1_7: J1.7 J1.8 R27.2 | length 647.5
  TOP LAYER w8: J1.7@992,2544.88 942,2494.88 J1.8@942,2444.88 1042.88,2344 v1(1149,2344)
  BOTTOM LAYER w8: v1(1149,2344) 1167,2344 1187,2364 1385,2364 1391.5,2370.5 R27.2@1391.5,2395
NetJ9_1: J9.1 J9.2 J9.3 J9.4 R62.2 | length 170
  TOP LAYER w15: J9.2@622.05,225.2 v1(622.05,267.69) ; v1(622.05,332.31) J9.1@622.05,374.8 ; J9.4@653.54,225.2 v1(653.54,267.69) ; v1(653.54,332.31) J9.3@653.54,374.8
NetJ9_45: J9.45 J9.46 R58.1 | length 267.8
  TOP LAYER w15: v1(1282,431) 1295,431 1314.96,411.04 J9.45@1314.96,374.8 J9.46@1314.96,225.2
  BOTTOM LAYER w15: R58.1@1275.5,393 1275.5,424.5 v1(1282,431)
NetL1_1: L1.1 U5.9 | length 44.4
  TOP LAYER w8: 1414,832 1415,831 U5.9@1415,788
NetR6_1: R6.1 U2.V16 | length 287.3
  TOP LAYER w4: U2.V16@820.2,1538.9 831.59,1550.29 844.29,1550.29 866,1572 866,1597 892,1623 892,1716 902,1726 925,1726 948,1703 R6.1@951.38,1703
NetR8_1: R8.1 U2.W16 | length 287
  TOP LAYER w4: U2.W16@839.88,1538.9 851.9,1538.9 879,1566 879,1593 907,1621 921,1621 927,1627 927,1640 922,1645 908.5,1645 903,1650.5 903,1683 910,1690 919.5,1690 927,1682.5 927,1671 946,1652 R8.1@951.38,1652
NetR19_2: R19.2 R49.2 U5.8 | length 106.4
  TOP LAYER w8: U5.8@1434.7,788 1434.7,819.7 1443,828 v1(1443,848)
  BOTTOM LAYER w15: v1(1550,844) R49.2@1550,886.5 ; R49.2@1550,893.5 R49.2@1550.41,893.5
NetR21_2: R21.2 U5.3 | length 89.7
  TOP LAYER w8: U5.3@1434.7,708 1434.7,660.3 ; 1440,628 1434.7,633.3 1434.7,660.3 ; 1440,655 1434.7,660.3
NetR22_1: R22.1 U5.5
NetR29_2: R29.2 T1.10 | length 110.4
  TOP LAYER w8: T1.10@1171.48,2219 1176.48,2214 v1(1227,2214)
  BOTTOM LAYER w8: R29.2@1179,2225.5 1215.5,2225.5 v1(1227,2214)
NetR34_2: R34.2 T1.15 | length 113.9
  TOP LAYER w8: v1(1119,1972) 1168.48,1972 T1.15@1171.48,1969
  BOTTOM LAYER w8: v1(1119,1972) 1119.5,1972.5 R34.2@1179,1972.5
NetR40_1: R40.1 U2.K17 | length 287.4
  TOP LAYER w4: v1@649.57,1550 654.13,1550 U2.K17@662.72,1558.58
  BOTTOM LAYER w4: v1(643,1550) 692,1599 731,1599 771,1639 804,1639 839,1604 R40.1@839,1580.62
NetR41_1: R41.1 U2.W15 | length 186.2
  TOP LAYER w4: U2.W15@839.88,1519.21 849.21,1519.21 v1(899,1569)
  BOTTOM LAYER w4: v1(899,1569) 899,1555 940,1514 R41.1@974.5,1514
NetR46_1: R46.1 U2.M16 | length 260.7
  TOP LAYER w4: v1@702.09,1514.87 U2.M16@702.09,1538.9 ; v1@702.11,1514.89 v1@703,1515.79
  BOTTOM LAYER w4: v1(703,1514) 687,1514 672.5,1499.5 672.5,1378.5 685,1366 713,1366 720,1359 R46.1@720,1336.62
NetR47_1: R47.1 U2.K15 | length 287.4
  TOP LAYER w4: U2.K15@662.72,1519.21 672.21,1519.21 v1(683,1530)
  BOTTOM LAYER w4: R47.1@674,1336.62 672.72,1337.91 672.72,1363.28 654,1382 632,1382 626,1388 626,1397 634,1405 656,1405 662.72,1411.72 662.72,1509.72 v1(683,1530)
NetR51_2: R51.2 U5.7 | length 140.2
  TOP LAYER w8: U5.7@1454.4,788 1454.4,810.4 1464,820
  TOP LAYER w15: 1464,820 1480,836 v1(1480,837)
  BOTTOM LAYER w15: R51.2@1437.5,900 1480,857.5 v1(1480,837)
NetR57_1: R57.1 R58.2 U6.5 | length 176.3
  TOP LAYER w20: U6.5@1294,483 1294,476 v1(1323,447)
  BOTTOM LAYER w15: v1(1323,447) 1338.5,431.5 R58.2@1338.5,393
  BOTTOM LAYER w20: R57.1@1288.5,490 1288.5,463.5 1305,447 v1(1323,447)
PD0/AIN15: U2.C2
PD1/T0CCP0: U2.C1
PE4: U2.A5
PF1/LED2: R48.1 U2.V6 | length 1373.3
  TOP LAYER w4: v1(493,1019) 517,995 981,995 v1(1036,1050) ; U2.V6@820.2,1342.05 831.46,1330.79 988.79,1330.79 996,1338 1017,1338 v1(1024,1331)
  BOTTOM LAYER w4: v1@1025,1330 1025,1305.79 1044,1286.79 1044,1058 v1(1036,1050)
  BOTTOM LAYER w8: R48.1@231,979.62 231,1003 247,1019 v1(493,1019)
PG0/PPS: J9.43 U2.N15 | length 1618.3
  TOP LAYER w4: U2.N15@721.77,1519.21 721.77,1497.23 742,1477 v1(742,1476) ; v1(903,744) 907,740 989,740 1016,713 1111,713 1138,740 1174,740 1190,724 1190,656 1174,640 1168,640 1162,634 1162,555 1182,535 1182,466 1225,423 1261,423 1282,402 ; J9.43@1282,376.27 J9.43@1283.46,374.8
  TOP LAYER w6: J9.43@1282,376.27 1282,402
  BOTTOM LAYER w4: v1(742,1476) 767,1476 848,1395 848,1271 891,1228 891,790 903,778 v1(903,744)
PP6: U2.B8
PQ7/LED_G: U2.M3
RESET_N: J9.22 TP6.1 U2.B9 | length 2772.2
  TOP LAYER w4: TP6.1@120,291 TP6.1@120,300 ; U2.B9@505.24,1401.1 467.1,1401.1 393,1327 393,1079 524,948 524,799 542,781 655,781 686,812 938,812 944,806 v1(972,806)
  TOP LAYER w6: TP6.1@120,291 170,241 239,241 329,151 459.94,151 495.94,115 855.01,115 937.01,197 J9.22@937.01,225.2 v1(937.01,264.96)
  BOTTOM LAYER w4: v1(937.01,264.96) 921,280.97 921,475 946,500 946,604 938,612 938,739.31 972,773.31 v1(972,806)
RS485-A: D1.3 J2.2 R25.2 U1.6 | length 547.4
  TOP LAYER w8: v1(456,2496) 469,2496 481.22,2508.22 U1.6@481.22,2564.28
  BOTTOM LAYER w8: R25.2@405,2537.09 414.91,2537.09 v1(456,2496) 465,2487 483.37,2487 515,2518.63 515,2775 J2.2@472,2818
RS485-B: D2.3 J2.1 R25.1 U1.7 | length 598.4
  TOP LAYER w8: U1.7@431.22,2564.28 431.22,2486.78 v1(456,2462)
  BOTTOM LAYER w8: R25.1@405,2422.91 416.91,2422.91 v1(456,2462) 465,2471 490,2471 531,2512 531,2777 J2.1@572,2818
RX+_RJ45: D3.3 J1.3 T1.11 | length 744.8
  TOP LAYER w7: D3.3@1014.59,2124.5 v1(1040.4,2124.5) 1040.4,2143.4 1048,2151 1067,2151 1090,2174 1090,2198 1098,2206 1115,2206 1152,2169 T1.11@1171.48,2169
  BOTTOM LAYER w7: v1(1040.4,2124.5) 1040.4,2141.4 1048,2149 1065,2149 1089,2173 1089,2363.47 1104,2378.47 1104,2492 1156.88,2544.88 J1.3@1192,2544.88
RX-_RJ45: D3.4 J1.6 T1.9 | length 687.5
  TOP LAYER w7: D3.4@1014.59,2199.31 v1(1039.6,2199.31) 1039.6,2182.93 1048.53,2174 1057.47,2174 1067,2183.53 1067,2207.53 1088.47,2229 1115,2229 1155,2269 T1.9@1171.48,2269
  BOTTOM LAYER w7: v1@1037.41,2197.12 1037.41,2180.59 1046,2172 1055.47,2172 1066,2182.53 1066,2373 1081,2388 1081,2489 1071,2499 1052,2499 1042,2489 J1.6@1042,2444.88
RX_CLK: J9.37 U2.V5 | length 1631.1
  TOP LAYER w4: U2.V5@820.2,1322.36 820.56,1322 828.93,1322 828.97,1321.96 833.94,1321.96 833.98,1322 860,1322 873,1309 1006,1309 1020,1295 1060,1295 1073,1308 1073,1347 v1(1072,1348) ; v1(1014,809) 1079.69,809 1097.69,827 1174,827 1208,793 1208,643 1188,623 v1(1177,623)
  TOP LAYER w6: J9.37@1188.98,374.8 v1(1188.98,414.57)
  BOTTOM LAYER w4: v1(1014,809) 1011,812 1011,918 996,933 996,1062 1017,1083 1017,1244 1009,1252 1009,1317 1002,1324 1002,1345 1013,1356 1022,1356 1036,1370 1062,1370 1072,1360 v1(1072,1348) ; v1(1177,623) 1167,613 1167,436.54 v1(1188.98,414.57)
RX_DV: J9.35 U2.U14 | length 1447.9
  TOP LAYER w4: v1(765,1513) 787.04,1513 U2.U14@800.51,1499.53 ; v1(914,581) 915,582 1088,582 1157.48,512.52 J9.35@1157.48,374.8
  BOTTOM LAYER w4: v1(765,1513) 858,1420 858,1277 899,1236 899,805 918,786 918,725 913,720 v1@913,582
RX_ER: J9.39 U2.V12 | length 1481.4
  TOP LAYER w4: U2.V12@820.2,1460.16 831.57,1448.79 858.21,1448.79 867,1440 1085,1440 1155,1370 1161,1370 v1(1194,1337) ; v1(1142,699) 1163,699 1182,680 1182,660.79 1169.21,648 1161,648 1154,641 1154,540 1171,523 1171,458 1220.47,408.53
  TOP LAYER w6: J9.39@1220.47,374.8 1220.47,408.53
  BOTTOM LAYER w4: v1(1142,699) 1151,708 1151,772 1185,806 1185,1302 1194,1311 v1(1194,1337)
RXD0: J9.31 U2.W12 | length 1630
  TOP LAYER w4: U2.W12@839.88,1460.16 858.84,1460.16 870,1449 1099,1449 v1(1154,1394) ; v1(1093,336) v1@1094.49,337.49
  TOP LAYER w6: v1@1094.49,337.49 J9.31@1094.49,374.8
  BOTTOM LAYER w4: v1(1093,336) 1116,359 1116,565 1086,595 1086,653 1109,676 1109,827 1114,832 1119,832 1129,822 1138,822 1143,827 1143,834 1134.5,842.5 1134.5,848.5 1138.5,852.5 1148.5,852.5 1152,856 1152,866 1146.5,871.5 1136,871.5 1131.33,876.17 1131.33,885.33 1136.5,890.5 1146.5,890.5 1151,895 1151,905 1146.5,909.5 1136.5,909.5 1131.33,914.67 1131.33,924 1135.83,928.5 1146,928.5 1151,933.5 1151,941 1146,946 1134,946 1130,950 1130,958 1134,962 1148,962 1151,965 1151,1311 1139,1323 1139,1379 v1(1154,1394)
RXD1: J9.33 U2.U15 | length 1640.9
  TOP LAYER w4: v1(784,1530) 789.72,1530 U2.U15@800.51,1519.21 ; v1(930,563) 1081,563 1125.98,518.02 1125.98,444 1118.98,437 1090,437 1084,431 1084,422 1089,417 1116.98,417 1125.98,408 J9.33@1125.98,374.8
  BOTTOM LAYER w4: v1(784,1530) 868,1446 868,1281 909,1240 909,1045 914,1040 931.44,1040 936.44,1035 936.44,1022.44 930,1016 915,1016 909,1010 909,1000 917,992 930,992 936.44,985.56 936.44,974.44 930,968 915,968 909,962 909,950 915,944 932.44,944 936.44,940 936.44,926.44 930,920 915,920 909,914 909,901 914,896 933,896 936.44,892.56 936.44,876.44 932,872 915,872 909,866 909,816 929,796 929,564 v1(930,563)
RXD2: J9.29 U2.V17 | length 1658.9
  TOP LAYER w4: U2.V17@820.2,1558.58 835.58,1558.58 844.35,1567.35 844.41,1567.35 850.8,1573.74 850.8,1573.8 855,1578 855,1610 v1(875,1630)
  TOP LAYER w6: v1(1063,335) J9.29@1062.99,374.8
  BOTTOM LAYER w4: v1(875,1630) 884,1621 884,1537 956,1465 1073,1465 1130,1408 1130,1320 1142,1308 1142,1298 1122,1278 1122,851.31 1099,828.31 1099,679 1078,658 1078,586 1089,575 1089,515 1082,508 1082,383 1063,364 v1(1063,335)
RXD3: J9.27 R24.1 U2.U19 | length 1604.4
  TOP LAYER w4: U2.U19@800.51,1597.95 830.56,1628 838,1628 v1(852,1642) ; R24.1@1022.62,459 R24.1@1025.62,462 ; v1(1056,462) 1051,462 v1@1057,456
  TOP LAYER w6: R24.1@1025.62,462 v1@1051,462 ; J9.27@1031.5,374.8 1031.5,399.5 1057,425 v1@1057,456
  BOTTOM LAYER w4: v1(852,1642) 852,1632 860,1624 860,1623.79 876,1607.79 876,1527 955,1448 1077,1448 1121,1404 1121,1321 1104,1304 1104,860 1079,835 1079,685 1059,665 1059,575 1071,563 1071,528 1056,513 v1(1056,462)
SPARE1: J3.1 U2.V7 | length 2882.6
  TOP LAYER w4: U2.V7@820.2,1361.73 832.46,1374 844,1374 856,1362 938,1362 949,1373 991,1373 1002,1362 1038,1362 v1(1048,1352) ; v1(1054,892) 1075,892 1169,986 1169,1129 1425,1385 v1(1434,1385)
  BOTTOM LAYER w4: v1(1048,1352) 1048,1343 1060,1331 1060,898 v1(1054,892) ; v1(1434,1385) 1426,1393 1335,1393 1326,1402 1326,1430 1531,1635 1531,1696 1611,1776 1611,2444.85 1725.07,2558.93
  BOTTOM LAYER w8: 1725.07,2558.93 J3.1@1766.63,2600.48
SPARE2: J3.3 U2.W7 | length 2475.8
  TOP LAYER w4: U2.W7@839.88,1361.73 849.61,1352 942,1352 953,1363 988,1363 998,1353 1025,1353 1045,1333 v1(1045,1317) ; v1(1040,972) 1096,1028 1096,1113.47 1520,1537.47 1520,1592 1540,1612 1555,1612 v1@1559,1608
  BOTTOM LAYER w4: v1(1040,972) 1052,984 1052,1310 v1(1045,1317) ; v1(1563,1603) 1563,1604 1551,1616 1551,1685 1634,1768 1634,2389.11 1738.94,2494.06
  BOTTOM LAYER w8: 1738.94,2494.06 J3.3@1766.63,2521.74
SPARE3: J3.5 U2.R3 | length 2358.6
  TOP LAYER w4: v1(755,1014) 958,1014 1008,1064 1008,1081 v1(1423,1496) ; U2.R3@761.14,1282.99 v1@761.14,1297.14
  BOTTOM LAYER w4: v1(755,1014) 769,1028 769,1276 763,1282 v1(763,1302) ; v1(1423,1496) 1423,1495 1463,1495 1482,1514 1482,1552 1498,1568 1566.31,1568 1588,1589.69 1588,1624 1569,1643 1569,1669 1658,1758 1658,2334.37 1736.82,2413.18
  BOTTOM LAYER w8: 1736.82,2413.18 J3.5@1766.63,2443
SPARE4: J3.7 U2.D7 | length 2723.6
  TOP LAYER w4: U2.D7@544.61,1361.73 555,1372.13 559.24,1372.13 566.77,1379.65 v1(570.23,1379.65) ; v1(600,908.44) 611.23,908.44 626,923.21 967.21,923.21 1080,1036 1080,1108.78 1505,1533.78 v1(1505,1551)
  BOTTOM LAYER w4: v1(570.23,1379.65) 589.89,1360 597.21,1360 606,1351.21 606,1316 589,1299 589,1289.28 588.72,1289 588.72,1276.57 589,1276.29 589,1026 579,1016 579,929.44 v1(600,908.44) ; v1@1503,1551 v1(1505,1551) 1506,1552 1561.63,1552 1599,1589.37 1599,1665 1682,1748 1682,2279.63 1738.69,2336.31
  BOTTOM LAYER w8: 1738.69,2336.31 J3.7@1766.63,2364.26
SPARE5: U2.B10
SPARE6: U2.B5
SPI0CS: J9.26 TP13.1 U2.U5 | length 2179.5
  TOP LAYER w4: v1(788,1304) 800.51,1316.51 U2.U5@800.51,1322.36 ; v1(795,622) 899,622 905,628 v1(962,628)
  TOP LAYER w6: TP13.1@240,180 281,139 454.97,139 490.97,103 906,103 1000,197 J9.26@1000,225.2 v1(1000,264.96)
  BOTTOM LAYER w4: v1(788,1304) 777,1293 777,1033 797,1013 797,727.79 791,721.79 791,650.69 796,645.69 796,623 v1(795,622) ; v1(962,628) 964,626 964,464 953,453 953,311.96 v1(1000,264.96)
SPI0SCK: J9.28 TP12.1 U2.T6 | length 2603
  TOP LAYER w4: v1(739,675) 783,675 789,669 841,669 859,687 912,687 918,681 v1(963,681) ; v1(760,1391) 749,1380 749,1354 755,1348 774.87,1348 U2.T6@780.83,1342.05
  TOP LAYER w6: TP12.1@120,180 173,127 450,127 486,91 927,91 1031.5,195.5 J9.28@1031.5,225.2 v1(1031.5,264.96)
  BOTTOM LAYER w4: v1(739,675) 750,686 750,740 775,765 775,950 705,1020 705,1210 743,1248 743,1374 v1(760,1391) ; v1(963,681) 963,669 977,655 977,435 983.5,428.5 983.5,312.95 v1(1031.5,264.96)
SPI0SDI: J9.32 TP18.1 U2.W4 | length 2410.4
  TOP LAYER w4: U2.W4@839.88,1302.68 888.56,1254 1076,1254 v1(1124,1302)
  TOP LAYER w6: TP18.1@240,60 247,67 979,67 1094.49,182.49 J9.32@1094.49,225.2 1094.49,259.51 1058.45,295.55 v1(1058.45,301)
  BOTTOM LAYER w4: v1(1058.45,301) 1047,312.45 1047,431 1073,457 1073,515 1080,522 1080,568 1068,580 1068,661 1089,682 1089,831 1112,854 1112,1290 v1(1124,1302)
SPI0SDO: J9.30 R60.2 TP17.1 U2.V4 | length 2436.1
  TOP LAYER w4: U2.V4@820.2,1302.68 831.48,1313.96 837.26,1313.96 837.3,1314 846,1314 874,1286 1000,1286 1015,1271 v1(1029,1271)
  TOP LAYER w6: TP17.1@120,60 158,98 263,98 282,79 944.99,79 1062.99,197 J9.30@1062.99,225.2 1062.99,264.96 v1(1031,297)
  BOTTOM LAYER w4: v1(1029,1271) 1035,1265 1035,1070.21 1019,1054.21 1019,945 1029,935 1029,764 1016,751 1016,311.95 1062.99,264.96 R60.2@1062.99,233
SPI3CS: J9.10 TP1.1 U2.E2 | length 1942.7
  TOP LAYER w4: v1(564.29,1201) 564.29,1249.46 564.48,1249.65 564.23,1249.9 564.23,1254.87 564.29,1254.94 U2.E2@564.29,1263.31 ; v1(583,661) 722,661 730,653 v1(758,653)
  TOP LAYER w6: TP1.1@360,540 420,480 420,277 522,175 723,175 748.03,200.03 J9.10@748.03,225.2 v1(748.03,264.96)
  BOTTOM LAYER w4: v1(564.29,1201) 580,1185.29 580,1125 569,1114 569,908 593,884 593,756 582,745 v1@582,662 ; v1@582,660 v1@582,662 ; v1(583,661) v1@582,662 ; v1(748.03,264.96) 748.03,276.97 743,282 743,387 763.03,407.03 763.03,628 758,633.03 v1(758,653)
SPI3SCK: J9.12 TP3.1 U2.E3 | length 1803.8
  TOP LAYER w4: v1(527,598) 544,581 777,581 v1@789,593 ; v1@547.92,1282.99 U2.E3@564.29,1282.99
  TOP LAYER w6: TP3.1@617,506 587,476 587,331 605,313 767,313 779.53,300.47 v1@779.53,266.47 ; J9.12@779.53,225.2 v1@779.53,266.47 ; v1(780,266) v1@779.53,266.47
  BOTTOM LAYER w4: v1(527,598) 528,598 528,762 518,772 518,1114 508,1124 508,1248 544,1284 v1(545,1284) ; v1(780,266) 780,287 796,303 796,567 791,572 v1(791,591)
SPI3SDI: J9.16 TP8.1 U2.U6 | length 1816.5
  TOP LAYER w6: TP8.1@360,300 361.85,300 510.85,151 796.52,151 842.52,197 J9.16@842.52,225.2 v1(842.52,264.96)
  TOP LAYER w8: v1(766,1328) 786.46,1328 U2.U6@800.51,1342.05
  BOTTOM LAYER w4: v1(766,1328) 788,1328 818,1298 818,1253 865,1206 865,772 871,766 871,657.53 881,647.53 881,533 851,503 851,461 857.52,454.48 857.52,279.96 v1(842.52,264.96)
SPI3SDO: J9.14 TP5.1 U2.H4 | length 2005.1
  TOP LAYER w4: v1(616,699) 617,698 746,698 750,694 750,693.79 758.79,685 816,685 v1@816.89,685.89 ; U2.H4@623.35,1302.68 639.32,1302.68 v1(643,1299)
  TOP LAYER w6: TP5.1@360,420 403,377 403,277 511,169 ; 511.03,169 517.03,163 777.02,163 811.02,197 J9.14@811.02,225.2 811.02,262.02 v1(842,293)
  BOTTOM LAYER w4: v1(616,699) 616,701 626,711 626,923.21 644,941.21 644,1004 622,1026 622,1171.69 649,1198.69 649,1256 643,1262 v1(643,1299) ; v1(817,686) 826,677 826,420.8 826.02,413.98 842,398 v1(842,293)
T_TRST: J7.10 R38.2 | length 2335.7
  TOP LAYER w4: v1(284,1331) 284,1269 324,1229 324,1084 228,988 228,741 276,693 351.89,693 359.89,685
  TOP LAYER w6: v1(424,1953) 467,1996 807,1996 920,1883 v1(920,1772)
  TOP LAYER w8: 359.89,685 J7.10@391.37,653.52
  BOTTOM LAYER w4: R38.2@964.53,1741.73 R38.2@965.47,1740.79
  BOTTOM LAYER w6: v1@422.5,1951.5 422.5,1633.5 374,1585 303,1585 281,1563 281,1474 266,1459 266,1349 v1(284,1331) ; v1(920,1772) 954.26,1772 964.53,1761.73 R38.2@964.53,1741.73 ; v1(284,1331) 288,1331 284,1327 v1(284,1331)
TCK: J7.4 R20.2 U2.B15 | length 831.9
  TOP LAYER w4: 424.63,923 433,931.37 433,1026 379,1080 379,1330 472,1423 472,1503 481.45,1512.45 498.47,1512.45 U2.B15@505.24,1519.21
  TOP LAYER w8: J7.4@391.37,889.74 424.63,923
  BOTTOM LAYER w8: J7.4@391.37,889.74 427.49,853.62 R20.2@477,853.62
TDI: J7.8 R52.2 U2.D14 | length 1296.8
  TOP LAYER w4: 360.63,763 351.63,772 276,772 241,807 241,987 334,1080 334,1234 301,1267 301,1347 425,1471 v1(456,1471)
  TOP LAYER w8: 360.63,763 J7.8@391.37,732.26 ; U2.D14@544.61,1499.53 544.61,1515.6 v1@547,1518
  BOTTOM LAYER w4: v1(456,1471) 454,1471 453,1472 457,1472 503,1518 547,1518 v1(545,1520)
  BOTTOM LAYER w6: R52.2@230,694.38 231.38,693 352.11,693
  BOTTOM LAYER w8: 352.11,693 J7.8@391.37,732.26
TDO: J7.6 R54.2 U2.C14 | length 1082.3
  TOP LAYER w4: 359.19,843.19 352.37,850 286.63,850 255,881.63 255,985 350,1080 350,1235 316,1269 316,1343 381,1408 v1(395,1408)
  TOP LAYER w8: 359.19,843.19 J7.6@391.37,811 ; U2.C14@524.92,1499.53 524.92,1480.08 v1(526,1479)
  BOTTOM LAYER w4: v1(395,1408) 455,1408 v1(526,1479)
  BOTTOM LAYER w8: J7.6@391.37,811 458.75,743.62 R54.2@478,743.62
TMS: J7.2 R17.2 U2.C15 | length 787.3
  TOP LAYER w4: 391.37,1026 391.37,1054.63 365,1081 365,1354 v1(455,1444)
  TOP LAYER w8: J7.2@391.37,968.48 391.37,1026 ; v1(524,1544) 524,1520.13 U2.C15@524.92,1519.21
  BOTTOM LAYER w4: v1(455,1444) 439,1460 439,1478 505,1544 v1(524,1544)
  BOTTOM LAYER w8: J7.2@391.51,968.62 R17.2@477,968.62
TX+_RJ45: D3.1 J1.1 T1.16 | length 1763.3
  TOP LAYER w7: D3.1@963.41,2124.5 938.6,2124.5 v1(938,2123.91) 938,2142 930,2150 920.53,2150 915,2144.47 915,2095.53 1133.53,1877 1213.47,1877 1237,1900.53 1237,1941 1232,1946 1219,1946 1192,1919 T1.16@1171.48,1919
  BOTTOM LAYER w7: v1(938,2123.91) 938,2140 928,2150 906,2150 871,2185 871,2552.53 957.47,2639 1202.53,2639 1253,2588.53 1253,2509.53 1260.53,2502 1284,2502 1291.5,2509.5 J1.1@1291.5,2544.38 ; J1.1@1268.74,2521.62 J1.1@1291.5,2544.38 ; J1.1@1291.5,2545.38 J1.1@1291.5,2544.38 ; J1.1@1292,2544.88 J1.1@1291.5,2544.38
